VERSION 5.7 ;
BUSBITCHARS "[]" ;
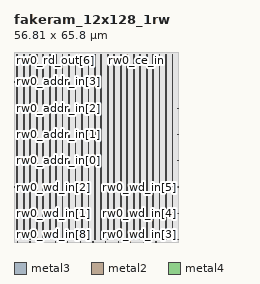
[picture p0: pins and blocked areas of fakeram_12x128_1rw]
MACRO fakeram_12x128_1rw
  FOREIGN fakeram_12x128_1rw 0 0 ;
  SYMMETRY X Y R90 ;
  SIZE 56.810 BY 65.800 ;
  CLASS BLOCK ;
  PIN rw0_wd_in[0]
    DIRECTION INPUT ;
    USE SIGNAL ;
    SHAPE ABUTMENT ;
    PORT
      LAYER metal3 ;
      RECT 0.000 0.805 0.210 0.875 ;
    END
  END rw0_wd_in[0]
  PIN rw0_wd_in[1]
    DIRECTION INPUT ;
    USE SIGNAL ;
    SHAPE ABUTMENT ;
    PORT
      LAYER metal3 ;
      RECT 0.000 9.905 0.210 9.975 ;
    END
  END rw0_wd_in[1]
  PIN rw0_wd_in[2]
    DIRECTION INPUT ;
    USE SIGNAL ;
    SHAPE ABUTMENT ;
    PORT
      LAYER metal3 ;
      RECT 0.000 19.005 0.210 19.075 ;
    END
  END rw0_wd_in[2]
  PIN rw0_wd_in[3]
    DIRECTION INPUT ;
    USE SIGNAL ;
    SHAPE ABUTMENT ;
    PORT
      LAYER metal3 ;
      RECT 56.600 0.805 56.810 0.875 ;
    END
  END rw0_wd_in[3]
  PIN rw0_wd_in[4]
    DIRECTION INPUT ;
    USE SIGNAL ;
    SHAPE ABUTMENT ;
    PORT
      LAYER metal3 ;
      RECT 56.600 9.905 56.810 9.975 ;
    END
  END rw0_wd_in[4]
  PIN rw0_wd_in[5]
    DIRECTION INPUT ;
    USE SIGNAL ;
    SHAPE ABUTMENT ;
    PORT
      LAYER metal3 ;
      RECT 56.600 19.005 56.810 19.075 ;
    END
  END rw0_wd_in[5]
  PIN rw0_wd_in[6]
    DIRECTION INPUT ;
    USE SIGNAL ;
    SHAPE ABUTMENT ;
    PORT
      LAYER metal2 ;
      RECT 1.105 0.000 1.175 0.210 ;
    END
  END rw0_wd_in[6]
  PIN rw0_wd_in[7]
    DIRECTION INPUT ;
    USE SIGNAL ;
    SHAPE ABUTMENT ;
    PORT
      LAYER metal2 ;
      RECT 5.475 0.000 5.545 0.210 ;
    END
  END rw0_wd_in[7]
  PIN rw0_wd_in[8]
    DIRECTION INPUT ;
    USE SIGNAL ;
    SHAPE ABUTMENT ;
    PORT
      LAYER metal2 ;
      RECT 9.845 0.000 9.915 0.210 ;
    END
  END rw0_wd_in[8]
  PIN rw0_wd_in[9]
    DIRECTION INPUT ;
    USE SIGNAL ;
    SHAPE ABUTMENT ;
    PORT
      LAYER metal2 ;
      RECT 14.215 0.000 14.285 0.210 ;
    END
  END rw0_wd_in[9]
  PIN rw0_wd_in[10]
    DIRECTION INPUT ;
    USE SIGNAL ;
    SHAPE ABUTMENT ;
    PORT
      LAYER metal2 ;
      RECT 18.585 0.000 18.655 0.210 ;
    END
  END rw0_wd_in[10]
  PIN rw0_wd_in[11]
    DIRECTION INPUT ;
    USE SIGNAL ;
    SHAPE ABUTMENT ;
    PORT
      LAYER metal2 ;
      RECT 22.955 0.000 23.025 0.210 ;
    END
  END rw0_wd_in[11]
  PIN rw0_rd_out[0]
    DIRECTION OUTPUT ;
    USE SIGNAL ;
    SHAPE ABUTMENT ;
    PORT
      LAYER metal2 ;
      RECT 27.325 0.000 27.395 0.210 ;
    END
  END rw0_rd_out[0]
  PIN rw0_rd_out[1]
    DIRECTION OUTPUT ;
    USE SIGNAL ;
    SHAPE ABUTMENT ;
    PORT
      LAYER metal2 ;
      RECT 31.695 0.000 31.765 0.210 ;
    END
  END rw0_rd_out[1]
  PIN rw0_rd_out[2]
    DIRECTION OUTPUT ;
    USE SIGNAL ;
    SHAPE ABUTMENT ;
    PORT
      LAYER metal2 ;
      RECT 36.065 0.000 36.135 0.210 ;
    END
  END rw0_rd_out[2]
  PIN rw0_rd_out[3]
    DIRECTION OUTPUT ;
    USE SIGNAL ;
    SHAPE ABUTMENT ;
    PORT
      LAYER metal2 ;
      RECT 40.435 0.000 40.505 0.210 ;
    END
  END rw0_rd_out[3]
  PIN rw0_rd_out[4]
    DIRECTION OUTPUT ;
    USE SIGNAL ;
    SHAPE ABUTMENT ;
    PORT
      LAYER metal2 ;
      RECT 44.805 0.000 44.875 0.210 ;
    END
  END rw0_rd_out[4]
  PIN rw0_rd_out[5]
    DIRECTION OUTPUT ;
    USE SIGNAL ;
    SHAPE ABUTMENT ;
    PORT
      LAYER metal2 ;
      RECT 49.175 0.000 49.245 0.210 ;
    END
  END rw0_rd_out[5]
  PIN rw0_rd_out[6]
    DIRECTION OUTPUT ;
    USE SIGNAL ;
    SHAPE ABUTMENT ;
    PORT
      LAYER metal2 ;
      RECT 1.105 65.590 1.175 65.800 ;
    END
  END rw0_rd_out[6]
  PIN rw0_rd_out[7]
    DIRECTION OUTPUT ;
    USE SIGNAL ;
    SHAPE ABUTMENT ;
    PORT
      LAYER metal2 ;
      RECT 6.995 65.590 7.065 65.800 ;
    END
  END rw0_rd_out[7]
  PIN rw0_rd_out[8]
    DIRECTION OUTPUT ;
    USE SIGNAL ;
    SHAPE ABUTMENT ;
    PORT
      LAYER metal2 ;
      RECT 12.885 65.590 12.955 65.800 ;
    END
  END rw0_rd_out[8]
  PIN rw0_rd_out[9]
    DIRECTION OUTPUT ;
    USE SIGNAL ;
    SHAPE ABUTMENT ;
    PORT
      LAYER metal2 ;
      RECT 18.775 65.590 18.845 65.800 ;
    END
  END rw0_rd_out[9]
  PIN rw0_rd_out[10]
    DIRECTION OUTPUT ;
    USE SIGNAL ;
    SHAPE ABUTMENT ;
    PORT
      LAYER metal2 ;
      RECT 24.665 65.590 24.735 65.800 ;
    END
  END rw0_rd_out[10]
  PIN rw0_rd_out[11]
    DIRECTION OUTPUT ;
    USE SIGNAL ;
    SHAPE ABUTMENT ;
    PORT
      LAYER metal2 ;
      RECT 30.555 65.590 30.625 65.800 ;
    END
  END rw0_rd_out[11]
  PIN rw0_addr_in[0]
    DIRECTION INPUT ;
    USE SIGNAL ;
    SHAPE ABUTMENT ;
    PORT
      LAYER metal3 ;
      RECT 0.000 28.105 0.210 28.175 ;
    END
  END rw0_addr_in[0]
  PIN rw0_addr_in[1]
    DIRECTION INPUT ;
    USE SIGNAL ;
    SHAPE ABUTMENT ;
    PORT
      LAYER metal3 ;
      RECT 0.000 37.205 0.210 37.275 ;
    END
  END rw0_addr_in[1]
  PIN rw0_addr_in[2]
    DIRECTION INPUT ;
    USE SIGNAL ;
    SHAPE ABUTMENT ;
    PORT
      LAYER metal3 ;
      RECT 0.000 46.305 0.210 46.375 ;
    END
  END rw0_addr_in[2]
  PIN rw0_addr_in[3]
    DIRECTION INPUT ;
    USE SIGNAL ;
    SHAPE ABUTMENT ;
    PORT
      LAYER metal3 ;
      RECT 0.000 55.405 0.210 55.475 ;
    END
  END rw0_addr_in[3]
  PIN rw0_addr_in[4]
    DIRECTION INPUT ;
    USE SIGNAL ;
    SHAPE ABUTMENT ;
    PORT
      LAYER metal3 ;
      RECT 56.600 28.105 56.810 28.175 ;
    END
  END rw0_addr_in[4]
  PIN rw0_addr_in[5]
    DIRECTION INPUT ;
    USE SIGNAL ;
    SHAPE ABUTMENT ;
    PORT
      LAYER metal3 ;
      RECT 56.600 37.205 56.810 37.275 ;
    END
  END rw0_addr_in[5]
  PIN rw0_addr_in[6]
    DIRECTION INPUT ;
    USE SIGNAL ;
    SHAPE ABUTMENT ;
    PORT
      LAYER metal3 ;
      RECT 56.600 46.305 56.810 46.375 ;
    END
  END rw0_addr_in[6]
  PIN rw0_we_in
    DIRECTION INPUT ;
    USE SIGNAL ;
    SHAPE ABUTMENT ;
    PORT
      LAYER metal2 ;
      RECT 36.445 65.590 36.515 65.800 ;
    END
  END rw0_we_in
  PIN rw0_ce_in
    DIRECTION INPUT ;
    USE SIGNAL ;
    SHAPE ABUTMENT ;
    PORT
      LAYER metal2 ;
      RECT 42.335 65.590 42.405 65.800 ;
    END
  END rw0_ce_in
  PIN rw0_clk
    DIRECTION INPUT ;
    USE SIGNAL ;
    SHAPE ABUTMENT ;
    PORT
      LAYER metal2 ;
      RECT 48.225 65.590 48.295 65.800 ;
    END
  END rw0_clk
  PIN VSS
    DIRECTION INOUT ;
    USE GROUND ;
    PORT
      LAYER metal4 ;
      RECT 1.000 0.840 1.280 64.960 ;
      RECT 3.240 0.840 3.520 64.960 ;
      RECT 5.480 0.840 5.760 64.960 ;
      RECT 7.720 0.840 8.000 64.960 ;
      RECT 9.960 0.840 10.240 64.960 ;
      RECT 12.200 0.840 12.480 64.960 ;
      RECT 14.440 0.840 14.720 64.960 ;
      RECT 16.680 0.840 16.960 64.960 ;
      RECT 18.920 0.840 19.200 64.960 ;
      RECT 21.160 0.840 21.440 64.960 ;
      RECT 23.400 0.840 23.680 64.960 ;
      RECT 25.640 0.840 25.920 64.960 ;
      RECT 27.880 0.840 28.160 64.960 ;
      RECT 30.120 0.840 30.400 64.960 ;
      RECT 32.360 0.840 32.640 64.960 ;
      RECT 34.600 0.840 34.880 64.960 ;
      RECT 36.840 0.840 37.120 64.960 ;
      RECT 39.080 0.840 39.360 64.960 ;
      RECT 41.320 0.840 41.600 64.960 ;
      RECT 43.560 0.840 43.840 64.960 ;
      RECT 45.800 0.840 46.080 64.960 ;
      RECT 48.040 0.840 48.320 64.960 ;
      RECT 50.280 0.840 50.560 64.960 ;
      RECT 52.520 0.840 52.800 64.960 ;
      RECT 54.760 0.840 55.040 64.960 ;
    END
  END VSS
  PIN VDD
    DIRECTION INOUT ;
    USE POWER ;
    PORT
      LAYER metal4 ;
      RECT 1.000 0.840 1.280 64.960 ;
      RECT 3.240 0.840 3.520 64.960 ;
      RECT 5.480 0.840 5.760 64.960 ;
      RECT 7.720 0.840 8.000 64.960 ;
      RECT 9.960 0.840 10.240 64.960 ;
      RECT 12.200 0.840 12.480 64.960 ;
      RECT 14.440 0.840 14.720 64.960 ;
      RECT 16.680 0.840 16.960 64.960 ;
      RECT 18.920 0.840 19.200 64.960 ;
      RECT 21.160 0.840 21.440 64.960 ;
      RECT 23.400 0.840 23.680 64.960 ;
      RECT 25.640 0.840 25.920 64.960 ;
      RECT 27.880 0.840 28.160 64.960 ;
      RECT 30.120 0.840 30.400 64.960 ;
      RECT 32.360 0.840 32.640 64.960 ;
      RECT 34.600 0.840 34.880 64.960 ;
      RECT 36.840 0.840 37.120 64.960 ;
      RECT 39.080 0.840 39.360 64.960 ;
      RECT 41.320 0.840 41.600 64.960 ;
      RECT 43.560 0.840 43.840 64.960 ;
      RECT 45.800 0.840 46.080 64.960 ;
      RECT 48.040 0.840 48.320 64.960 ;
      RECT 50.280 0.840 50.560 64.960 ;
      RECT 52.520 0.840 52.800 64.960 ;
      RECT 54.760 0.840 55.040 64.960 ;
    END
  END VDD
  OBS
    LAYER metal1 ;
    RECT 0 0 56.810 65.800 ;
    LAYER metal2 ;
    RECT 0 0 56.810 65.800 ;
    LAYER metal3 ;
    RECT 0 0 56.810 65.800 ;
    LAYER metal4 ;
    RECT 0 0 56.810 65.800 ;
    LAYER OVERLAP ;
    RECT 0 0 56.810 65.800 ;
  END
END fakeram_12x128_1rw

END LIBRARY
